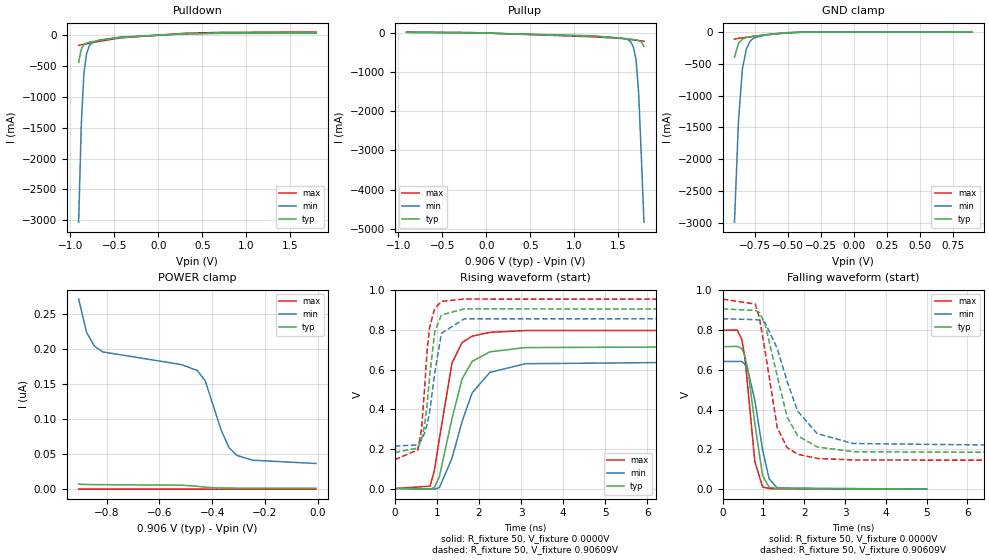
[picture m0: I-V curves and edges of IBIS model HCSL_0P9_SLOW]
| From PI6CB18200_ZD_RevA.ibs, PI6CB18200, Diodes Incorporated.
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[Model]   HCSL_0P9_SLOW
Model_type Output
Vref=0.9000V
Vmeas=900mV
| variable   typ   min   max
C_comp   2.200pF   2.170pF   2.230pF
[Voltage Range]   0.90609V   0.85650V   0.95550V
[POWER Clamp Reference]   0.90609V   0.85650V   0.95550V
[GND Clamp Reference]   0.0000V   0.0000V   0.0000V
[Pullup Reference]   0.90609V   0.85650V   0.95550V
[Pulldown Reference]   0.0000V   0.0000V   0.0000V
[Temperature Range]   25   85   -40
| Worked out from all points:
|   slope of the pulldown table from 0 to 0.136 V, typ, clamps not added: 12.1 ohm
|   slope of the pullup table from 0 to 0.136 V, typ, clamps not added: 13.2 ohm
|   GND clamp passes 1 mA (typ) near -0.37 V on its own axis
|   falling waveform, R_fixture 50, V_fixture 0.0000V: 20-80 % time 262ps typ, 311ps min, 217ps max; typ from 0.717 V to 0 V
|   rising waveform, R_fixture 50, V_fixture 0.0000V: 20-80 % time 477ps typ, 588ps min, 371ps max; typ from 0 V to 0.717 V
|   falling waveform, R_fixture 50, V_fixture 0.90609V: 20-80 % time 517ps typ, 675ps min, 375ps max; typ from 0.906 V to 0.182 V
|   rising waveform, R_fixture 50, V_fixture 0.90609V: 20-80 % time 210ps typ, 255ps min, 174ps max; typ from 0.182 V to 0.906 V
[GND Clamp]
| Voltage   I(typ)   I(min)   I(max)
-906.1mV  -394.8mA   -2.992A    -111.1mA
-876.1mV  -181.4mA   -1.409A    -98.21mA
-846.1mV  -110.3mA   -583mA     -89.83mA
-816.1mV  -84.16mA   -264.3mA   -82.58mA
-786.1mV  -71.98mA   -139.6mA   -75.25mA
-756.1mV  -63.63mA   -88.35mA   -67.26mA
-666.1mV  -41.95mA   -43.55mA   -41.94mA
-516.1mV  -12.97mA   -15.56mA   -9.674mA
-396.1mV  -1.762mA   -3.322mA   -556.7uA
893.9mV   1.274nA    37.22nA    5.408pA
[POWER Clamp]
| Voltage   I(typ)   I(min)   I(max)
-906.1mV  7.102nA    272nA      64.05pA
-876.1mV  6.695nA    224.4nA    62.63pA
-846.1mV  6.537nA    204.6nA    61.28pA
-816.1mV  6.464nA    196.5nA    59.93pA
-516.1mV  5.725nA    178.2nA    42.48pA
-456.1mV  4.154nA    169.7nA    33.31pA
-426.1mV  2.718nA    154.9nA    31.21pA
-366.1mV  1.642nA    84.73nA    27.91pA
-336.1mV  1.538nA    59.52nA    26.32pA
-306.1mV  1.492nA    48.22nA    24.74pA
-246.1mV  1.442nA    41.44nA    21.59pA
-6.09mV   1.286nA    36.73nA    8.971pA
[Pulldown]
| Voltage   I(typ)   I(min)   I(max)
-906.1mV  -441mA     -3.03A     -170.1mA
-876.1mV  -227.7mA   -1.447A    -157.3mA
-846.1mV  -156.6mA   -620.6mA   -149mA
-816.1mV  -130.6mA   -302mA     -142mA
-786.1mV  -118.6mA   -177.3mA   -135mA
-756.1mV  -110.1mA   -125.9mA   -127mA
-666.1mV  -86.67mA   -79.52mA   -99.89mA
-426.1mV  -37.54mA   -32.71mA   -46.06mA
293.9mV   20.99mA    16.43mA    28.11mA
713.9mV   33.61mA    26.75mA    43.5mA
1.794V    37.21mA    29.87mA    47.47mA
[Pullup]
| Voltage   I(typ)   I(min)   I(max)
-906.1mV  18.82mA    14.78mA    24.99mA
-156.1mV  9.295mA    7.313mA    12.41mA
1.224V    -81.1mA    -71.37mA   -96.53mA
1.554V    -133.6mA   -133mA     -141.2mA
1.614V    -148.7mA   -170.9mA   -158.1mA
1.644V    -156.3mA   -224.4mA   -167.1mA
1.674V    -164.3mA   -354.5mA   -176.2mA
1.704V    -173.8mA   -686.8mA   -185.2mA
1.734V    -189.7mA   -1.549A    -193.6mA
1.764V    -227.7mA   -3.147A    -201.3mA
1.794V    -336.2mA   -4.832A    -208.5mA
[Falling Waveform]
R_fixture = 50
V_fixture = 0.0000V
V_fixture_min = 0.0000V
V_fixture_max = 0.0000V
|   Time   V(typ)   V(min)   V(max)
0s        716.5mV    641.8mV    798.5mV
360ps     717.6mV    642mV      799.6mV
470ps     706.6mV    642.3mV    753.1mV
540ps     672.8mV    629.4mV    670.8mV
620ps     602.4mV    595.9mV    506.7mV
790ps     327.9mV    446.7mV    137.6mV
980ps     67.51mV    197.7mV    11.4mV
1.14ns    9.752mV    52.26mV    2.978mV
1.34ns    2.764mV    6.174mV    1.739mV
5ns       21.81uV    40.36uV    12.77uV
[Rising Waveform]
R_fixture = 50
V_fixture = 0.0000V
V_fixture_min = 0.0000V
V_fixture_max = 0.0000V
|   Time   V(typ)   V(min)   V(max)
0s        6.392uV    7.808uV    5.434uV
840ps     -3.191mV   -2.875mV   11.96mV
940ps     4.599mV    -2.373mV   88.63mV
1.06ns    59.24mV    4.519mV    250.1mV
1.36ns    352.5mV    152.3mV    632.8mV
1.6ns     553.3mV    338.1mV    736.9mV
1.84ns    641.5mV    483.3mV    768.8mV
2.26ns    689.6mV    586.1mV    788mV
3.1ns     711.2mV    629.8mV    796.9mV
10ns      716.5mV    641.8mV    798.5mV
[Falling Waveform]
R_fixture = 50
V_fixture = 0.90609V
V_fixture_min = 0.85650V
V_fixture_max = 0.95550V
|   Time   V(typ)   V(min)   V(max)
0s        906.1mV    856.5mV    955.5mV
800ps     898.2mV    852.1mV    930.1mV
900ps     888.7mV    849.8mV    863.7mV
1.04ns    830.6mV    837.7mV    695.8mV
1.34ns    567.6mV    706.5mV    307.3mV
1.58ns    363.7mV    542.6mV    209.2mV
1.84ns    267.8mV    391.7mV    175.4mV
2.32ns    212mV      278.9mV    154.6mV
3.2ns     188.4mV    229.5mV    146.6mV
10ns      182.3mV    213.9mV    145.1mV
[Rising Waveform]
R_fixture = 50
V_fixture = 0.90609V
V_fixture_min = 0.85650V
V_fixture_max = 0.95550V
|   Time   V(typ)   V(min)   V(max)
0s        182.3mV    213.9mV    145.1mV
550ps     204.2mV    220.5mV    195.5mV
640ps     250.8mV    246.9mV    304.4mV
710ps     318.8mV    280.7mV    508mV
770ps     422.6mV    323.2mV    700.1mV
830ps     566.3mV    385.5mV    814.2mV
950ps     789.9mV    583.3mV    908.1mV
1.11ns    876mV      783.2mV    944.4mV
1.65ns    906.5mV    856mV      955.9mV
7ns       906.1mV    856.5mV    955.5mV
[Ramp]
| variable   typ   min   max
dV/dt_r   0.42991V/478.47p   0.38507V/588.19p   0.47912V/371.25p
dV/dt_f   0.43427V/517.36p   0.38554V/674.88p   0.48626V/375.34p
R_load = 50
